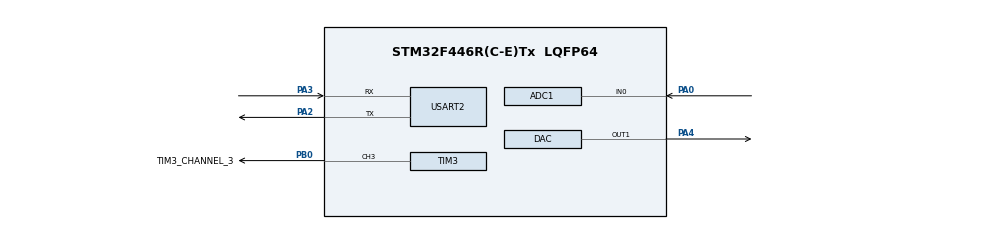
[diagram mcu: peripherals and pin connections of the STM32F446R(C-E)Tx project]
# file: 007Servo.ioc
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ADC1.Channel-0\#ChannelRegularConversion=ADC_CHANNEL_0
ADC1.NbrOfConversionFlag=1
ADC1.Rank-0\#ChannelRegularConversion=1
ADC1.SamplingTime-0\#ChannelRegularConversion=ADC_SAMPLETIME_3CYCLES
ADC1.master=1
Dma.ADC1.0.Direction=DMA_PERIPH_TO_MEMORY
Dma.ADC1.0.FIFOMode=DMA_FIFOMODE_DISABLE
Dma.ADC1.0.Instance=DMA2_Stream0
Dma.ADC1.0.MemDataAlignment=DMA_MDATAALIGN_HALFWORD
Dma.ADC1.0.MemInc=DMA_MINC_ENABLE
Dma.ADC1.0.Mode=DMA_NORMAL
Dma.ADC1.0.PeriphDataAlignment=DMA_PDATAALIGN_HALFWORD
Dma.ADC1.0.PeriphInc=DMA_PINC_DISABLE
Dma.ADC1.0.Priority=DMA_PRIORITY_LOW
Dma.Request0=ADC1
Mcu.Family=STM32F4
Mcu.Name=STM32F446R(C-E)Tx
Mcu.Package=LQFP64
NVIC.DMA2_Stream0_IRQn=true\:0\:0\:false\:false\:true\:false\:true\:true
NVIC.PriorityGroup=NVIC_PRIORITYGROUP_4
NVIC.USART2_IRQn=true\:0\:0\:false\:false\:true\:true\:true\:true
PA0-WKUP.Signal=ADCx_IN0
PA13.Signal=SYS_JTMS-SWDIO
PA14.Signal=SYS_JTCK-SWCLK
PA2.Mode=Asynchronous
PA2.Signal=USART2_TX
PA3.Mode=Asynchronous
PA3.Signal=USART2_RX
PA4.Signal=COMP_DAC1_group
PB0.GPIO_Label=TIM3_CHANNEL_3
PB0.Signal=S_TIM3_CH3
ProjectManager.HeapSize=0x200
ProjectManager.StackSize=0x400
ProjectManager.TargetToolchain=STM32CubeIDE
RCC.AHBFreq_Value=50000000
RCC.APB1CLKDivider=RCC_HCLK_DIV2
RCC.APB1Freq_Value=25000000
RCC.APB1TimFreq_Value=50000000
RCC.APB2Freq_Value=50000000
RCC.APB2TimFreq_Value=50000000
RCC.CortexFreq_Value=50000000
RCC.HCLKFreq_Value=50000000
RCC.PLLM=8
RCC.PLLN=50
RCC.SYSCLKFreq_VALUE=50000000
RCC.SYSCLKSource=RCC_SYSCLKSOURCE_PLLRCLK
RCC.USBFreq_Value=50000000
RCC.VCOOutputFreq_Value=100000000
SH.ADCx_IN0.0=ADC1_IN0,IN0
SH.COMP_DAC1_group.0=DAC_OUT1,DAC_OUT1
SH.S_TIM3_CH3.0=TIM3_CH3,PWM Generation3 CH3
TIM3.Channel-PWM\ Generation3\ CH3=TIM_CHANNEL_3
TIM3.OCMode_PWM-PWM\ Generation3\ CH3=TIM_OCMODE_PWM1
TIM3.Period=200-1
TIM3.Prescaler=5000-1
TIM3.Pulse-PWM\ Generation3\ CH3=20
USART2.VirtualMode=VM_ASYNC
VP_TIM3_VS_ClockSourceINT.Mode=Internal
board=custom

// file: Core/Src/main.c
/* USER CODE BEGIN Header */
/**
  ******************************************************************************
  * @file           : main.c
  * @brief          : Main program body
  ******************************************************************************
  * @attention
  *
  * Copyright (c) 2025 STMicroelectronics.
  * All rights reserved.
  *
  * This software is licensed under terms that can be found in the LICENSE file
  * in the root directory of this software component.
  * If no LICENSE file comes with this software, it is provided AS-IS.
  *
  ******************************************************************************
  */
/* USER CODE END Header */
#include "main.h"

 ADC_HandleTypeDef hadc1;
DMA_HandleTypeDef hdma_adc1;

DAC_HandleTypeDef hdac;

TIM_HandleTypeDef htim3;

UART_HandleTypeDef huart2;

void SystemClock_Config(void);
static void MX_GPIO_Init(void);
static void MX_DMA_Init(void);
static void MX_ADC1_Init(void);
static void MX_DAC_Init(void);
static void MX_TIM3_Init(void);
static void MX_USART2_UART_Init(void);

int main(void)
{

  /* MCU Configuration--------------------------------------------------------*/

  /* Reset of all peripherals, Initializes the Flash interface and the Systick. */
  HAL_Init();

  /* Configure the system clock */
  SystemClock_Config();

  /* Initialize all configured peripherals */
  MX_GPIO_Init();
  MX_DMA_Init();
  MX_ADC1_Init();
  MX_DAC_Init();
  MX_TIM3_Init();
  MX_USART2_UART_Init();
  /* USER CODE BEGIN 2 */
  HAL_TIM_PWM_Start(&htim3, TIM_CHANNEL_3);
  /* USER CODE END 2 */

  /* Infinite loop */
  while (1)
  {

  }
}

void SystemClock_Config(void)
{
  RCC_OscInitTypeDef RCC_OscInitStruct = {0};
  RCC_ClkInitTypeDef RCC_ClkInitStruct = {0};

  /** Configure the main internal regulator output voltage
  */
  __HAL_RCC_PWR_CLK_ENABLE();
  __HAL_PWR_VOLTAGESCALING_CONFIG(PWR_REGULATOR_VOLTAGE_SCALE3);

  /** Initializes the RCC Oscillators according to the specified parameters
  * in the RCC_OscInitTypeDef structure.
  */
  RCC_OscInitStruct.OscillatorType = RCC_OSCILLATORTYPE_HSI;
  RCC_OscInitStruct.HSIState = RCC_HSI_ON;
  RCC_OscInitStruct.HSICalibrationValue = RCC_HSICALIBRATION_DEFAULT;
  RCC_OscInitStruct.PLL.PLLState = RCC_PLL_NONE;
  if (HAL_RCC_OscConfig(&RCC_OscInitStruct) != HAL_OK)
  {
    Error_Handler();
  }

  /** Initializes the CPU, AHB and APB buses clocks
  */
  RCC_ClkInitStruct.ClockType = RCC_CLOCKTYPE_HCLK|RCC_CLOCKTYPE_SYSCLK
                              |RCC_CLOCKTYPE_PCLK1|RCC_CLOCKTYPE_PCLK2;
  RCC_ClkInitStruct.SYSCLKSource = RCC_SYSCLKSOURCE_HSI;
  RCC_ClkInitStruct.AHBCLKDivider = RCC_SYSCLK_DIV1;
  RCC_ClkInitStruct.APB1CLKDivider = RCC_HCLK_DIV1;
  RCC_ClkInitStruct.APB2CLKDivider = RCC_HCLK_DIV1;

  if (HAL_RCC_ClockConfig(&RCC_ClkInitStruct, FLASH_LATENCY_0) != HAL_OK)
  {
    Error_Handler();
  }
}

static void MX_ADC1_Init(void)
{

  ADC_ChannelConfTypeDef sConfig = {0};

  /** Configure the global features of the ADC (Clock, Resolution, Data Alignment and number of conversion)
  */
  hadc1.Instance = ADC1;
  hadc1.Init.ClockPrescaler = ADC_CLOCK_SYNC_PCLK_DIV2;
  hadc1.Init.Resolution = ADC_RESOLUTION_12B;
  hadc1.Init.ScanConvMode = DISABLE;
  hadc1.Init.ContinuousConvMode = DISABLE;
  hadc1.Init.DiscontinuousConvMode = DISABLE;
  hadc1.Init.ExternalTrigConvEdge = ADC_EXTERNALTRIGCONVEDGE_NONE;
  hadc1.Init.ExternalTrigConv = ADC_SOFTWARE_START;
  hadc1.Init.DataAlign = ADC_DATAALIGN_RIGHT;
  hadc1.Init.NbrOfConversion = 1;
  hadc1.Init.DMAContinuousRequests = DISABLE;
  hadc1.Init.EOCSelection = ADC_EOC_SINGLE_CONV;
  if (HAL_ADC_Init(&hadc1) != HAL_OK)
  {
    Error_Handler();
  }

  /** Configure for the selected ADC regular channel its corresponding rank in the sequencer and its sample time.
  */
  sConfig.Channel = ADC_CHANNEL_0;
  sConfig.Rank = 1;
  sConfig.SamplingTime = ADC_SAMPLETIME_3CYCLES;
  if (HAL_ADC_ConfigChannel(&hadc1, &sConfig) != HAL_OK)
  {
    Error_Handler();
  }

}

static void MX_DAC_Init(void)
{

  DAC_ChannelConfTypeDef sConfig = {0};

  /** DAC Initialization
  */
  hdac.Instance = DAC;
  if (HAL_DAC_Init(&hdac) != HAL_OK)
  {
    Error_Handler();
  }

  /** DAC channel OUT1 config
  */
  sConfig.DAC_Trigger = DAC_TRIGGER_NONE;
  sConfig.DAC_OutputBuffer = DAC_OUTPUTBUFFER_ENABLE;
  if (HAL_DAC_ConfigChannel(&hdac, &sConfig, DAC_CHANNEL_1) != HAL_OK)
  {
    Error_Handler();
  }

}

static void MX_TIM3_Init(void)
{

  TIM_ClockConfigTypeDef sClockSourceConfig = {0};
  TIM_MasterConfigTypeDef sMasterConfig = {0};
  TIM_OC_InitTypeDef sConfigOC = {0};

  htim3.Instance = TIM3;
  htim3.Init.Prescaler = 8399;
  htim3.Init.CounterMode = TIM_COUNTERMODE_UP;
  htim3.Init.Period = 19;
  htim3.Init.ClockDivision = TIM_CLOCKDIVISION_DIV1;
  htim3.Init.AutoReloadPreload = TIM_AUTORELOAD_PRELOAD_DISABLE;
  if (HAL_TIM_Base_Init(&htim3) != HAL_OK)
  {
    Error_Handler();
  }
  sClockSourceConfig.ClockSource = TIM_CLOCKSOURCE_INTERNAL;
  if (HAL_TIM_ConfigClockSource(&htim3, &sClockSourceConfig) != HAL_OK)
  {
    Error_Handler();
  }
  if (HAL_TIM_PWM_Init(&htim3) != HAL_OK)
  {
    Error_Handler();
  }
  sMasterConfig.MasterOutputTrigger = TIM_TRGO_RESET;
  sMasterConfig.MasterSlaveMode = TIM_MASTERSLAVEMODE_DISABLE;
  if (HAL_TIMEx_MasterConfigSynchronization(&htim3, &sMasterConfig) != HAL_OK)
  {
    Error_Handler();
  }
  sConfigOC.OCMode = TIM_OCMODE_PWM1;
  sConfigOC.Pulse = 1;
  sConfigOC.OCPolarity = TIM_OCPOLARITY_HIGH;
  sConfigOC.OCFastMode = TIM_OCFAST_DISABLE;
  if (HAL_TIM_PWM_ConfigChannel(&htim3, &sConfigOC, TIM_CHANNEL_3) != HAL_OK)
  {
    Error_Handler();
  }
  /* USER CODE BEGIN TIM3_Init 2 */
  //  htim3.Init.Period = 19; показывает длину всего периода
  // sConfigOC.Pulse = 2 показывает длину высокого напряжения в ШИМ
  /* USER CODE END TIM3_Init 2 */
  HAL_TIM_MspPostInit(&htim3);

}

static void MX_USART2_UART_Init(void)
{

  huart2.Instance = USART2;
  huart2.Init.BaudRate = 115200;
  huart2.Init.WordLength = UART_WORDLENGTH_8B;
  huart2.Init.StopBits = UART_STOPBITS_1;
  huart2.Init.Parity = UART_PARITY_NONE;
  huart2.Init.Mode = UART_MODE_TX_RX;
  huart2.Init.HwFlowCtl = UART_HWCONTROL_NONE;
  huart2.Init.OverSampling = UART_OVERSAMPLING_16;
  if (HAL_UART_Init(&huart2) != HAL_OK)
  {
    Error_Handler();
  }

}

static void MX_DMA_Init(void)
{

  /* DMA controller clock enable */
  __HAL_RCC_DMA2_CLK_ENABLE();

  /* DMA interrupt init */
  /* DMA2_Stream0_IRQn interrupt configuration */
  HAL_NVIC_SetPriority(DMA2_Stream0_IRQn, 0, 0);
  HAL_NVIC_EnableIRQ(DMA2_Stream0_IRQn);

}

static void MX_GPIO_Init(void)
{

  /* GPIO Ports Clock Enable */
  __HAL_RCC_GPIOA_CLK_ENABLE();
  __HAL_RCC_GPIOB_CLK_ENABLE();

}

void Error_Handler(void)
{
  __disable_irq();
  while (1)
  {
  }
}
